VERSION 5.7 ;
  NOWIREEXTENSIONATPIN ON ;
  DIVIDERCHAR "/" ;
  BUSBITCHARS "[]" ;
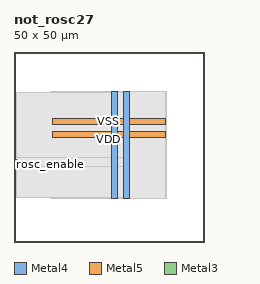
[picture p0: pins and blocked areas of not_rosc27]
MACRO not_rosc27
  CLASS BLOCK ;
  FOREIGN not_rosc27 ;
  ORIGIN 0.000 0.000 ;
  SIZE 50.000 BY 50.000 ;
  PIN VDD
    DIRECTION INOUT ;
    USE POWER ;
    PORT
      LAYER Metal4 ;
        RECT 25.600 11.460 27.200 39.500 ;
    END
    PORT
      LAYER Metal5 ;
        RECT 10.080 27.610 39.760 29.210 ;
    END
  END VDD
  PIN VSS
    DIRECTION INOUT ;
    USE GROUND ;
    PORT
      LAYER Metal4 ;
        RECT 28.900 11.460 30.500 39.500 ;
    END
    PORT
      LAYER Metal5 ;
        RECT 10.080 30.910 39.760 32.510 ;
    END
  END VSS
  PIN rosc_enable
    DIRECTION INPUT ;
    USE SIGNAL ;
    ANTENNAGATEAREA 1.057000 ;
    PORT
      LAYER Metal3 ;
        RECT 0.000 20.160 0.560 20.720 ;
    END
  END rosc_enable
  PIN rosc_out
    DIRECTION OUTPUT ;
    USE SIGNAL ;
    ANTENNAGATEAREA 1.102000 ;
    ANTENNADIFFAREA 0.897600 ;
    PORT
      LAYER Metal3 ;
        RECT 0.000 21.280 0.560 21.840 ;
    END
  END rosc_out
  OBS
      LAYER Nwell ;
        RECT 9.650 11.330 40.190 39.630 ;
      LAYER Metal1 ;
        RECT 10.080 11.460 39.760 39.500 ;
      LAYER Metal2 ;
        RECT 11.900 11.570 30.360 39.390 ;
      LAYER Metal3 ;
        RECT 0.560 22.140 30.410 39.340 ;
        RECT 0.860 19.860 30.410 22.140 ;
        RECT 0.560 11.620 30.410 19.860 ;
  END
END not_rosc27
END LIBRARY

